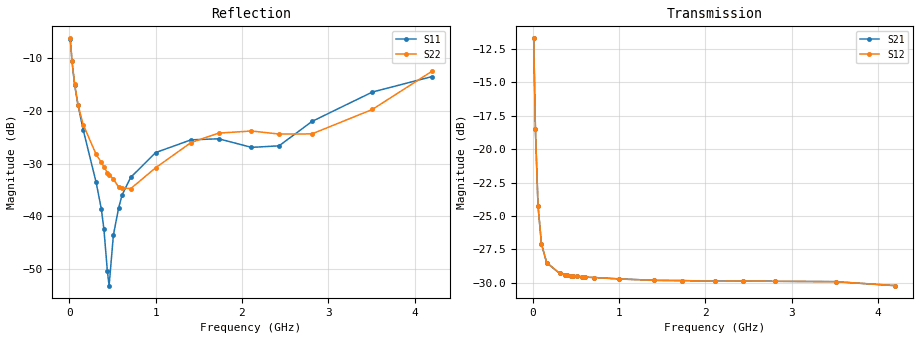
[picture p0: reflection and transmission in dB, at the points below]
! Integrated Device Technology
! Corporate Headquarters
! 6024 Silver Creek Valley Road
! San Jose, CA 95138  USA
! Phone:  1-408-284-8200
! Toll Free:  1-800-223-1366
! Webpage:  http://www.idt.com/
! Timing and RF Division
! 515 Groton Road, Suite 102
! Westford, MA 01886-6024
! Device:  F1950
! Description: 7-bit 0.25 dB Digital Step Attenuator
! Frequency:  150.0 -  4000.00 MHz
! Package:  4x4 mm Thin QFN Plastic Package: 24 pin
! Ports:  2 RF, 12 DC
!  Pin  1  = D0
!  Pin  2  = VDD
!  Pin  3  = Vmode
!  Pin  4  = GND
!  Pin  5  = RF1  =  Port 1
!  Pin  6  = GND
!  Pin  7  = GND
!  Pin  8  = GND
!  Pin  9  = GND
!  Pin 10  = GND
!  Pin 11  = GND
!  Pin 12  = GND
!  Pin 13  = GND
!  Pin 14  = RF2  =  Port 2
!  Pin 15  = GND
!  Pin 16  = LE
!  Pin 17  = CLK
!  Pin 18  = DATE
!  Pin 19  = D6
!  Pin 20  = D5
!  Pin 21  = D4
!  Pin 22  = D3
!  Pin 23  = D2
!  Pin 24  = D1
! State:  115
! Atten State:  28.75 dB
! Voltage:  +5.00 Volts
! Current:  Not Measured mA
! Data:  The device was measured on a the F195X evaluation board which has
!  individual transmission lines to the RF pins.  Data was collected
!  using a calibrated network analyzer.  The evaluation board was
!  de-embedded using a TRL calibration technique.
!  The reference plane is the edge of the package pin.
! Misc:  Board 2019
!  Action Tracker AT0250
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# GHz S dB R 50
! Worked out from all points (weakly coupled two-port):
!   420 points, 10 MHz to 4.2 GHz, reference 50 ohm
!   highest |S21| = -11.74 dB at 10 MHz (marker M1); lowest = -30.2 dB at 4.2 GHz (marker M2)
!   lowest |S11| = -53.1 dB at 460 MHz (marker M3), VSWR 1.00, Z = 49.8 - j0.0595 ohm
!   |S11| at or under -10 dB: 27.2 MHz to end of sweep
!   |S22| runs from -35.0 to -6.2 dB; largest |S21 - S12| = 8.6e-05
!   S11 on the Smith chart (normalised r, x): 10 MHz: 2.03, -1.18; 30 MHz: 1.27, -0.65; 60 MHz: 1.11, -0.36; 370 MHz: 1.01, -0.02; 4.2 GHz: 0.69, +0.17
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0.01  -6.33 -27.7  -11.74 -38.7  -11.73 -38.7  -6.21 -28.6
0.03  -10.55 -51.3  -18.52 -61.2  -18.52 -61.2  -10.46 -52.9
0.06  -15.01 -64.0  -24.22 -55.2  -24.22 -55.2  -14.78 -65.6
0.1  -18.89 -70.8  -27.09 -41.7  -27.09 -41.7  -18.85 -71.1
0.16  -23.58 -72.9  -28.49 -29.6  -28.48 -29.6  -22.59 -76.3
0.31  -33.54 -73.5  -29.29 -18.4  -29.29 -18.4  -28.23 -84.1
0.37  -38.59 -72.7  -29.39 -16.6  -29.38 -16.6  -29.72 -86.9
0.4  -42.45 -79.1  -29.42 -15.9  -29.42 -15.9  -30.57 -88.4
0.44  -50.37 -109.7  -29.46 -15.3  -29.46 -15.2  -31.69 -93.3
0.46  -53.13 -164.3  -29.48 -15.0  -29.48 -15.0  -32.09 -96.7
0.51  -43.50 143.7  -29.51 -14.4  -29.51 -14.4  -32.91 -102.5
0.57  -38.42 136.8  -29.54 -14.1  -29.54 -14.1  -34.42 -113.4
0.61  -35.94 137.8  -29.57 -13.9  -29.56 -13.9  -34.54 -121.8
0.71  -32.58 138.6  -29.60 -13.7  -29.60 -13.7  -34.73 -141.5
1  -27.87 147.9  -29.70 -14.4  -29.71 -14.4  -30.75 178.1
1.41  -25.46 162.5  -29.81 -16.3  -29.81 -16.4  -25.97 159.8
1.73  -25.26 167.7  -29.83 -18.1  -29.83 -18.1  -24.19 151.4
2.11  -26.89 157.2  -29.87 -21.1  -29.88 -21.2  -23.78 141.5
2.43  -26.60 126.0  -29.87 -23.1  -29.87 -23.1  -24.36 130.6
2.81  -21.98 105.3  -29.88 -26.3  -29.88 -26.3  -24.34 115.2
3.51  -16.40 117.3  -29.91 -31.6  -29.91 -31.7  -19.70 112.7
4.2  -13.47 145.4  -30.21 -34.5  -30.20 -34.5  -12.47 126.8
